VERSION 5.7 ;
  DIVIDERCHAR "/" ;
  BUSBITCHARS "[]" ;
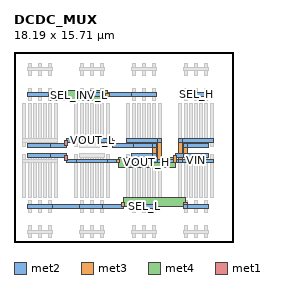
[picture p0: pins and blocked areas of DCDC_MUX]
MACRO DCDC_MUX
  CLASS BLOCK ;
  ORIGIN 0 0 ;
  FOREIGN DCDC_MUX 0 0 ;
  SIZE 18.19 BY 15.71 ;
  PIN SEL_H
    DIRECTION INOUT ;
    USE SIGNAL ;
    PORT
      LAYER met2 ;
        RECT 14.02 12.04 16.08 12.32 ;
    END
  END SEL_H
  PIN SEL_INV_H
    DIRECTION INOUT ;
    USE SIGNAL ;
    PORT
      LAYER met2 ;
        RECT 1.12 2.8 3.18 3.08 ;
      LAYER met2 ;
        RECT 5.42 2.8 7.48 3.08 ;
      LAYER met2 ;
        RECT 14.02 2.8 16.08 3.08 ;
      LAYER met2 ;
        RECT 3.01 2.8 5.59 3.08 ;
      LAYER met2 ;
        RECT 7.31 2.8 9.03 3.08 ;
      LAYER met3 ;
        RECT 8.89 2.94 9.17 3.3 ;
      LAYER met4 ;
        RECT 9.03 2.9 14.19 3.7 ;
      LAYER met3 ;
        RECT 14.05 2.94 14.33 3.3 ;
      LAYER met2 ;
        RECT 14.03 2.8 14.35 3.08 ;
    END
  END SEL_INV_H
  PIN SEL_INV_L
    DIRECTION INOUT ;
    USE SIGNAL ;
    PORT
      LAYER met2 ;
        RECT 9.72 12.04 11.78 12.32 ;
      LAYER met2 ;
        RECT 1.12 12.04 3.18 12.32 ;
      LAYER met2 ;
        RECT 5.42 12.04 7.48 12.32 ;
      LAYER met2 ;
        RECT 7.74 12.04 9.89 12.32 ;
      LAYER met3 ;
        RECT 7.6 12.019 7.88 12.261 ;
      LAYER met4 ;
        RECT 3.01 11.7 7.74 12.5 ;
      LAYER met3 ;
        RECT 2.87 12.019 3.15 12.261 ;
      LAYER met2 ;
        RECT 2.85 12.04 3.17 12.32 ;
      LAYER met4 ;
        RECT 5.425 11.7 5.755 12.5 ;
      LAYER met3 ;
        RECT 5.45 12.019 5.73 12.261 ;
      LAYER met2 ;
        RECT 5.43 12.04 5.75 12.32 ;
    END
  END SEL_INV_L
  PIN SEL_L
    DIRECTION INOUT ;
    USE SIGNAL ;
    PORT
      LAYER met2 ;
        RECT 9.72 2.8 11.78 3.08 ;
    END
  END SEL_L
  PIN VIN
    DIRECTION INOUT ;
    USE SIGNAL ;
    PORT
      LAYER met2 ;
        RECT 13.59 6.58 16.51 6.86 ;
      LAYER met2 ;
        RECT 13.59 8.26 16.51 8.54 ;
      LAYER met2 ;
        RECT 13.6 6.58 13.92 6.86 ;
      LAYER met3 ;
        RECT 13.62 6.72 13.9 8.4 ;
      LAYER met2 ;
        RECT 13.6 8.26 13.92 8.54 ;
      LAYER met2 ;
        RECT 9.29 6.58 12.21 6.86 ;
      LAYER met2 ;
        RECT 9.29 8.26 12.21 8.54 ;
      LAYER met2 ;
        RECT 11.88 6.58 12.2 6.86 ;
      LAYER met3 ;
        RECT 11.9 6.72 12.18 8.4 ;
      LAYER met2 ;
        RECT 11.88 8.26 12.2 8.54 ;
      LAYER met2 ;
        RECT 12.04 6.58 13.76 6.86 ;
    END
  END VIN
  PIN VOUT_H
    DIRECTION INOUT ;
    USE SIGNAL ;
    PORT
      LAYER met2 ;
        RECT 4.99 6.58 7.91 6.86 ;
      LAYER met2 ;
        RECT 1.12 7 3.18 7.28 ;
      LAYER met2 ;
        RECT 4.3 6.58 5.16 6.86 ;
      LAYER met1 ;
        RECT 4.175 6.72 4.425 7.14 ;
      LAYER met2 ;
        RECT 3.01 7 4.3 7.28 ;
      LAYER met2 ;
        RECT 14.02 7 16.08 7.28 ;
      LAYER met2 ;
        RECT 14.02 7.84 16.08 8.12 ;
      LAYER met2 ;
        RECT 14.03 7 14.35 7.28 ;
      LAYER met3 ;
        RECT 14.05 7.14 14.33 7.98 ;
      LAYER met2 ;
        RECT 14.03 7.84 14.35 8.12 ;
      LAYER met2 ;
        RECT 7.74 6.58 8.6 6.86 ;
      LAYER met3 ;
        RECT 8.46 6.539 8.74 6.781 ;
      LAYER met4 ;
        RECT 8.6 6.2 13.33 7 ;
      LAYER met3 ;
        RECT 13.19 6.6 13.47 7.14 ;
      LAYER met2 ;
        RECT 13.33 7 14.19 7.28 ;
    END
  END VOUT_H
  PIN VOUT_L
    DIRECTION INOUT ;
    USE SIGNAL ;
    PORT
      LAYER met2 ;
        RECT 9.72 7 11.78 7.28 ;
      LAYER met2 ;
        RECT 9.72 7.84 11.78 8.12 ;
      LAYER met2 ;
        RECT 11.45 7 11.77 7.28 ;
      LAYER met3 ;
        RECT 11.47 7.14 11.75 7.98 ;
      LAYER met2 ;
        RECT 11.45 7.84 11.77 8.12 ;
      LAYER met2 ;
        RECT 4.99 8.26 7.91 8.54 ;
      LAYER met2 ;
        RECT 1.12 7.84 3.18 8.12 ;
      LAYER met2 ;
        RECT 4.3 8.26 5.16 8.54 ;
      LAYER met1 ;
        RECT 4.175 7.98 4.425 8.4 ;
      LAYER met2 ;
        RECT 3.01 7.84 4.3 8.12 ;
      LAYER met2 ;
        RECT 8.17 7.84 9.89 8.12 ;
      LAYER met1 ;
        RECT 8.045 7.98 8.295 8.4 ;
      LAYER met2 ;
        RECT 7.74 8.26 8.17 8.54 ;
    END
  END VOUT_L
  OBS
  LAYER met1 ;
        RECT 5.465 3.695 5.715 7.225 ;
  LAYER met1 ;
        RECT 5.465 2.435 5.715 3.445 ;
  LAYER met1 ;
        RECT 5.465 0.335 5.715 1.345 ;
  LAYER met1 ;
        RECT 5.035 3.695 5.285 7.225 ;
  LAYER met1 ;
        RECT 5.895 3.695 6.145 7.225 ;
  LAYER met1 ;
        RECT 6.325 3.695 6.575 7.225 ;
  LAYER met1 ;
        RECT 6.325 2.435 6.575 3.445 ;
  LAYER met1 ;
        RECT 6.325 0.335 6.575 1.345 ;
  LAYER met1 ;
        RECT 6.755 3.695 7.005 7.225 ;
  LAYER met1 ;
        RECT 7.185 3.695 7.435 7.225 ;
  LAYER met1 ;
        RECT 7.185 2.435 7.435 3.445 ;
  LAYER met1 ;
        RECT 7.185 0.335 7.435 1.345 ;
  LAYER met1 ;
        RECT 7.615 3.695 7.865 7.225 ;
  LAYER met2 ;
        RECT 5.42 0.7 7.48 0.98 ;
  LAYER met2 ;
        RECT 5.42 7 7.48 7.28 ;
  LAYER met2 ;
        RECT 5.42 2.8 7.48 3.08 ;
  LAYER met2 ;
        RECT 4.99 6.58 7.91 6.86 ;
  LAYER met1 ;
        RECT 2.885 3.695 3.135 7.225 ;
  LAYER met1 ;
        RECT 2.885 2.435 3.135 3.445 ;
  LAYER met1 ;
        RECT 2.885 0.335 3.135 1.345 ;
  LAYER met1 ;
        RECT 3.315 3.695 3.565 7.225 ;
  LAYER met1 ;
        RECT 2.455 3.695 2.705 7.225 ;
  LAYER met1 ;
        RECT 2.025 3.695 2.275 7.225 ;
  LAYER met1 ;
        RECT 2.025 2.435 2.275 3.445 ;
  LAYER met1 ;
        RECT 2.025 0.335 2.275 1.345 ;
  LAYER met1 ;
        RECT 1.595 3.695 1.845 7.225 ;
  LAYER met1 ;
        RECT 1.165 3.695 1.415 7.225 ;
  LAYER met1 ;
        RECT 1.165 2.435 1.415 3.445 ;
  LAYER met1 ;
        RECT 1.165 0.335 1.415 1.345 ;
  LAYER met1 ;
        RECT 0.735 3.695 0.985 7.225 ;
  LAYER met2 ;
        RECT 1.12 0.7 3.18 0.98 ;
  LAYER met2 ;
        RECT 1.12 7 3.18 7.28 ;
  LAYER met2 ;
        RECT 1.12 2.8 3.18 3.08 ;
  LAYER met2 ;
        RECT 0.69 6.58 3.61 6.86 ;
  LAYER met1 ;
        RECT 14.065 3.695 14.315 7.225 ;
  LAYER met1 ;
        RECT 14.065 2.435 14.315 3.445 ;
  LAYER met1 ;
        RECT 14.065 0.335 14.315 1.345 ;
  LAYER met1 ;
        RECT 13.635 3.695 13.885 7.225 ;
  LAYER met1 ;
        RECT 14.495 3.695 14.745 7.225 ;
  LAYER met1 ;
        RECT 14.925 3.695 15.175 7.225 ;
  LAYER met1 ;
        RECT 14.925 2.435 15.175 3.445 ;
  LAYER met1 ;
        RECT 14.925 0.335 15.175 1.345 ;
  LAYER met1 ;
        RECT 15.355 3.695 15.605 7.225 ;
  LAYER met1 ;
        RECT 15.785 3.695 16.035 7.225 ;
  LAYER met1 ;
        RECT 15.785 2.435 16.035 3.445 ;
  LAYER met1 ;
        RECT 15.785 0.335 16.035 1.345 ;
  LAYER met1 ;
        RECT 16.215 3.695 16.465 7.225 ;
  LAYER met2 ;
        RECT 14.02 0.7 16.08 0.98 ;
  LAYER met2 ;
        RECT 14.02 7 16.08 7.28 ;
  LAYER met2 ;
        RECT 14.02 2.8 16.08 3.08 ;
  LAYER met2 ;
        RECT 13.59 6.58 16.51 6.86 ;
  LAYER met1 ;
        RECT 14.065 7.895 14.315 11.425 ;
  LAYER met1 ;
        RECT 14.065 11.675 14.315 12.685 ;
  LAYER met1 ;
        RECT 14.065 13.775 14.315 14.785 ;
  LAYER met1 ;
        RECT 13.635 7.895 13.885 11.425 ;
  LAYER met1 ;
        RECT 14.495 7.895 14.745 11.425 ;
  LAYER met1 ;
        RECT 14.925 7.895 15.175 11.425 ;
  LAYER met1 ;
        RECT 14.925 11.675 15.175 12.685 ;
  LAYER met1 ;
        RECT 14.925 13.775 15.175 14.785 ;
  LAYER met1 ;
        RECT 15.355 7.895 15.605 11.425 ;
  LAYER met1 ;
        RECT 15.785 7.895 16.035 11.425 ;
  LAYER met1 ;
        RECT 15.785 11.675 16.035 12.685 ;
  LAYER met1 ;
        RECT 15.785 13.775 16.035 14.785 ;
  LAYER met1 ;
        RECT 16.215 7.895 16.465 11.425 ;
  LAYER met2 ;
        RECT 14.02 14.14 16.08 14.42 ;
  LAYER met2 ;
        RECT 14.02 7.84 16.08 8.12 ;
  LAYER met2 ;
        RECT 14.02 12.04 16.08 12.32 ;
  LAYER met2 ;
        RECT 13.59 8.26 16.51 8.54 ;
  LAYER met1 ;
        RECT 11.485 3.695 11.735 7.225 ;
  LAYER met1 ;
        RECT 11.485 2.435 11.735 3.445 ;
  LAYER met1 ;
        RECT 11.485 0.335 11.735 1.345 ;
  LAYER met1 ;
        RECT 11.915 3.695 12.165 7.225 ;
  LAYER met1 ;
        RECT 11.055 3.695 11.305 7.225 ;
  LAYER met1 ;
        RECT 10.625 3.695 10.875 7.225 ;
  LAYER met1 ;
        RECT 10.625 2.435 10.875 3.445 ;
  LAYER met1 ;
        RECT 10.625 0.335 10.875 1.345 ;
  LAYER met1 ;
        RECT 10.195 3.695 10.445 7.225 ;
  LAYER met1 ;
        RECT 9.765 3.695 10.015 7.225 ;
  LAYER met1 ;
        RECT 9.765 2.435 10.015 3.445 ;
  LAYER met1 ;
        RECT 9.765 0.335 10.015 1.345 ;
  LAYER met1 ;
        RECT 9.335 3.695 9.585 7.225 ;
  LAYER met2 ;
        RECT 9.72 0.7 11.78 0.98 ;
  LAYER met2 ;
        RECT 9.72 7 11.78 7.28 ;
  LAYER met2 ;
        RECT 9.72 2.8 11.78 3.08 ;
  LAYER met2 ;
        RECT 9.29 6.58 12.21 6.86 ;
  LAYER met1 ;
        RECT 11.485 7.895 11.735 11.425 ;
  LAYER met1 ;
        RECT 11.485 11.675 11.735 12.685 ;
  LAYER met1 ;
        RECT 11.485 13.775 11.735 14.785 ;
  LAYER met1 ;
        RECT 11.915 7.895 12.165 11.425 ;
  LAYER met1 ;
        RECT 11.055 7.895 11.305 11.425 ;
  LAYER met1 ;
        RECT 10.625 7.895 10.875 11.425 ;
  LAYER met1 ;
        RECT 10.625 11.675 10.875 12.685 ;
  LAYER met1 ;
        RECT 10.625 13.775 10.875 14.785 ;
  LAYER met1 ;
        RECT 10.195 7.895 10.445 11.425 ;
  LAYER met1 ;
        RECT 9.765 7.895 10.015 11.425 ;
  LAYER met1 ;
        RECT 9.765 11.675 10.015 12.685 ;
  LAYER met1 ;
        RECT 9.765 13.775 10.015 14.785 ;
  LAYER met1 ;
        RECT 9.335 7.895 9.585 11.425 ;
  LAYER met2 ;
        RECT 9.72 14.14 11.78 14.42 ;
  LAYER met2 ;
        RECT 9.72 7.84 11.78 8.12 ;
  LAYER met2 ;
        RECT 9.72 12.04 11.78 12.32 ;
  LAYER met2 ;
        RECT 9.29 8.26 12.21 8.54 ;
  LAYER met1 ;
        RECT 5.465 7.895 5.715 11.425 ;
  LAYER met1 ;
        RECT 5.465 11.675 5.715 12.685 ;
  LAYER met1 ;
        RECT 5.465 13.775 5.715 14.785 ;
  LAYER met1 ;
        RECT 5.035 7.895 5.285 11.425 ;
  LAYER met1 ;
        RECT 5.895 7.895 6.145 11.425 ;
  LAYER met1 ;
        RECT 6.325 7.895 6.575 11.425 ;
  LAYER met1 ;
        RECT 6.325 11.675 6.575 12.685 ;
  LAYER met1 ;
        RECT 6.325 13.775 6.575 14.785 ;
  LAYER met1 ;
        RECT 6.755 7.895 7.005 11.425 ;
  LAYER met1 ;
        RECT 7.185 7.895 7.435 11.425 ;
  LAYER met1 ;
        RECT 7.185 11.675 7.435 12.685 ;
  LAYER met1 ;
        RECT 7.185 13.775 7.435 14.785 ;
  LAYER met1 ;
        RECT 7.615 7.895 7.865 11.425 ;
  LAYER met2 ;
        RECT 5.42 14.14 7.48 14.42 ;
  LAYER met2 ;
        RECT 5.42 7.84 7.48 8.12 ;
  LAYER met2 ;
        RECT 5.42 12.04 7.48 12.32 ;
  LAYER met2 ;
        RECT 4.99 8.26 7.91 8.54 ;
  LAYER met1 ;
        RECT 2.885 7.895 3.135 11.425 ;
  LAYER met1 ;
        RECT 2.885 11.675 3.135 12.685 ;
  LAYER met1 ;
        RECT 2.885 13.775 3.135 14.785 ;
  LAYER met1 ;
        RECT 3.315 7.895 3.565 11.425 ;
  LAYER met1 ;
        RECT 2.455 7.895 2.705 11.425 ;
  LAYER met1 ;
        RECT 2.025 7.895 2.275 11.425 ;
  LAYER met1 ;
        RECT 2.025 11.675 2.275 12.685 ;
  LAYER met1 ;
        RECT 2.025 13.775 2.275 14.785 ;
  LAYER met1 ;
        RECT 1.595 7.895 1.845 11.425 ;
  LAYER met1 ;
        RECT 1.165 7.895 1.415 11.425 ;
  LAYER met1 ;
        RECT 1.165 11.675 1.415 12.685 ;
  LAYER met1 ;
        RECT 1.165 13.775 1.415 14.785 ;
  LAYER met1 ;
        RECT 0.735 7.895 0.985 11.425 ;
  LAYER met2 ;
        RECT 1.12 14.14 3.18 14.42 ;
  LAYER met2 ;
        RECT 1.12 7.84 3.18 8.12 ;
  LAYER met2 ;
        RECT 1.12 12.04 3.18 12.32 ;
  LAYER met2 ;
        RECT 0.69 8.26 3.61 8.54 ;
  END
END DCDC_MUX
